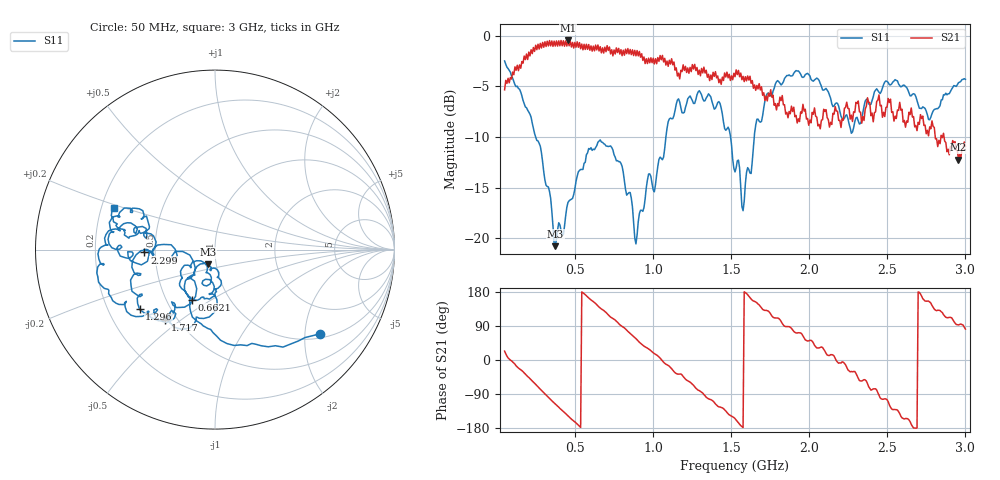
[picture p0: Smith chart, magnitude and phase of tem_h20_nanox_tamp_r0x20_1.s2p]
! nanovna_capture.py 2026-10-26T21:17:00+0900
! NanoVNA-F_V2 fw 0.6.0 SN 4A3639384505514B
! cal: load open short thru cal'ed  over 50000000-3000000000 Hz, 201 points
! points 401, avg 4
! TEM h=20, tampered Nano X, flat back down, 0 deg, moved 20 mm across the cell (right seen from PORT 1)
# HZ S RI R 50
! S12 and S22 are not measured (written as 0)
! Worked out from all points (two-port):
!   401 points, 50 MHz to 3 GHz, reference 50 ohm
!   highest |S21| = -0.46 dB at 455.6 MHz (marker M1); lowest = -12.2 dB at 2.956 GHz (marker M2)
!   |S21| within 3 dB of the highest: 112.6 MHz to 1.152 GHz (1.039 GHz wide, 164 % of centre); 1.246 GHz to 1.285 GHz (39.62 MHz wide, 3.13 % of centre) (the widest 2 of 12)
!   lowest |S11| = -20.8 dB at 374.5 MHz (marker M3), VSWR 1.20, Z = 45.6 - j7.62 ohm
!   |S11| at or under -10 dB: 249 MHz to 1.082 GHz (833.5 MHz wide, 125 % of centre); 1.497 GHz to 1.648 GHz (151.7 MHz wide, 9.65 % of centre)
!   S12 and S22 are empty: the file has one direction only
!   S11 on the Smith chart (normalised r, x): 50 MHz: 1.12, -2.40; 662.1 MHz: 0.67, -0.41; 1.296 GHz: 0.33, -0.31; 1.717 GHz: 0.43, -0.44; 2.299 GHz: 0.44, -0.02; 3 GHz: 0.25, +0.19
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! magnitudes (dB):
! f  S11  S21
! 50 MHz  -2.5  -5.3
! 271.2 MHz  -10.6  -1.3
! 374.5 MHz  -20.8  -1.0
! 455.6 MHz  -16.5  -0.5
! 544.1 MHz  -13.2  -0.8
! 662.1 MHz  -10.3  -1.1
! 794.9 MHz  -12.6  -1.4
! 890.8 MHz  -20.5  -2.0
! 971.9 MHz  -13.6  -2.2
! 1.038 GHz  -12.2  -2.5
! 1.156 GHz  -6.3  -4.0
! 1.296 GHz  -5.4  -3.4
! 1.429 GHz  -6.7  -4.3
! 1.525 GHz  -13.4  -4.0
! 1.577 GHz  -17.3  -4.0
! 1.717 GHz  -6.4  -6.4
! 2.019 GHz  -4.4  -7.6
! 2.299 GHz  -8.1  -6.6
! 2.513 GHz  -4.8  -6.6
! 2.771 GHz  -8.3  -9.0
! 2.956 GHz  -4.6  -12.2
! 3 GHz  -4.3  -10.9
